# Generated by FakeRAM 2.0
VERSION 5.7 ;
BUSBITCHARS "[]" ;
PROPERTYDEFINITIONS
  MACRO width INTEGER ;
  MACRO depth INTEGER ;
  MACRO banks INTEGER ;
END PROPERTYDEFINITIONS
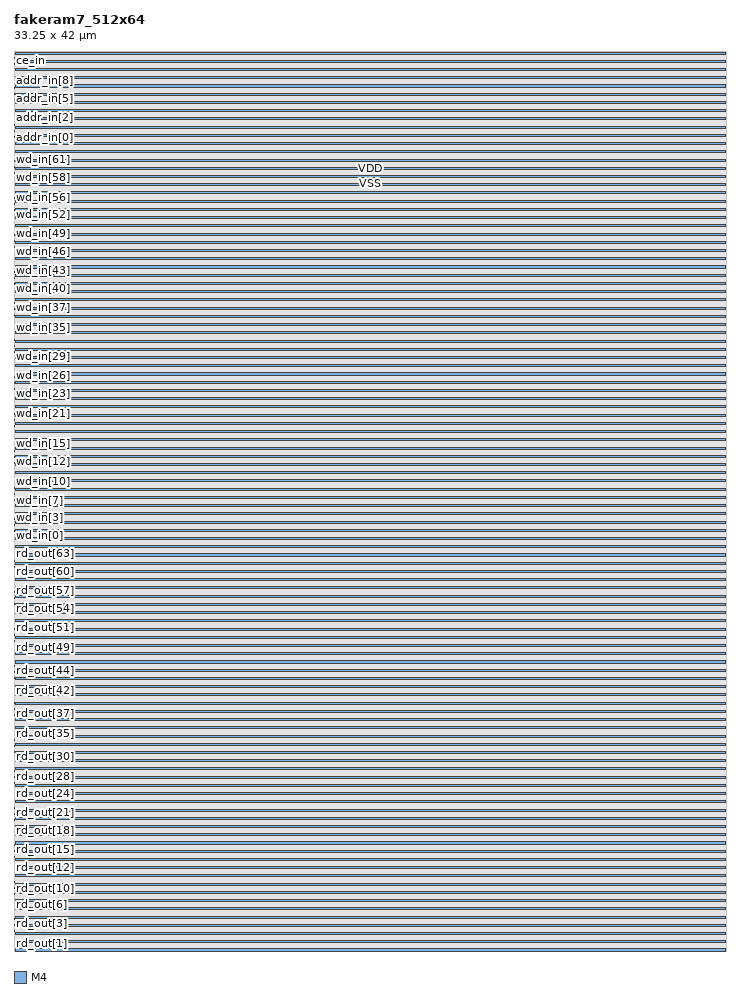
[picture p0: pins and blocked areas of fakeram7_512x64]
MACRO fakeram7_512x64
  PROPERTY width 64 ;
  PROPERTY depth 512 ;
  PROPERTY banks 4 ;
  FOREIGN fakeram7_512x64 0 0 ;
  SYMMETRY X Y R90 ;
  SIZE 33.2500 BY 42.0000 ;
  CLASS BLOCK ;
  PIN rd_out[0]
    DIRECTION OUTPUT ;
    USE SIGNAL ;
    PORT
      LAYER M4 ;
      RECT 0.00000 0.04800 0.02400 0.07200 ;
    END
  END rd_out[0]
  PIN rd_out[1]
    DIRECTION OUTPUT ;
    USE SIGNAL ;
    PORT
      LAYER M4 ;
      RECT 0.00000 0.33600 0.02400 0.36000 ;
    END
  END rd_out[1]
  PIN rd_out[2]
    DIRECTION OUTPUT ;
    USE SIGNAL ;
    PORT
      LAYER M4 ;
      RECT 0.00000 0.62400 0.02400 0.64800 ;
    END
  END rd_out[2]
  PIN rd_out[3]
    DIRECTION OUTPUT ;
    USE SIGNAL ;
    PORT
      LAYER M4 ;
      RECT 0.00000 0.91200 0.02400 0.93600 ;
    END
  END rd_out[3]
  PIN rd_out[4]
    DIRECTION OUTPUT ;
    USE SIGNAL ;
    PORT
      LAYER M4 ;
      RECT 0.00000 1.20000 0.02400 1.22400 ;
    END
  END rd_out[4]
  PIN rd_out[5]
    DIRECTION OUTPUT ;
    USE SIGNAL ;
    PORT
      LAYER M4 ;
      RECT 0.00000 1.48800 0.02400 1.51200 ;
    END
  END rd_out[5]
  PIN rd_out[6]
    DIRECTION OUTPUT ;
    USE SIGNAL ;
    PORT
      LAYER M4 ;
      RECT 0.00000 1.77600 0.02400 1.80000 ;
    END
  END rd_out[6]
  PIN rd_out[7]
    DIRECTION OUTPUT ;
    USE SIGNAL ;
    PORT
      LAYER M4 ;
      RECT 0.00000 2.06400 0.02400 2.08800 ;
    END
  END rd_out[7]
  PIN rd_out[8]
    DIRECTION OUTPUT ;
    USE SIGNAL ;
    PORT
      LAYER M4 ;
      RECT 0.00000 2.35200 0.02400 2.37600 ;
    END
  END rd_out[8]
  PIN rd_out[9]
    DIRECTION OUTPUT ;
    USE SIGNAL ;
    PORT
      LAYER M4 ;
      RECT 0.00000 2.64000 0.02400 2.66400 ;
    END
  END rd_out[9]
  PIN rd_out[10]
    DIRECTION OUTPUT ;
    USE SIGNAL ;
    PORT
      LAYER M4 ;
      RECT 0.00000 2.92800 0.02400 2.95200 ;
    END
  END rd_out[10]
  PIN rd_out[11]
    DIRECTION OUTPUT ;
    USE SIGNAL ;
    PORT
      LAYER M4 ;
      RECT 0.00000 3.21600 0.02400 3.24000 ;
    END
  END rd_out[11]
  PIN rd_out[12]
    DIRECTION OUTPUT ;
    USE SIGNAL ;
    PORT
      LAYER M4 ;
      RECT 0.00000 3.50400 0.02400 3.52800 ;
    END
  END rd_out[12]
  PIN rd_out[13]
    DIRECTION OUTPUT ;
    USE SIGNAL ;
    PORT
      LAYER M4 ;
      RECT 0.00000 3.79200 0.02400 3.81600 ;
    END
  END rd_out[13]
  PIN rd_out[14]
    DIRECTION OUTPUT ;
    USE SIGNAL ;
    PORT
      LAYER M4 ;
      RECT 0.00000 4.08000 0.02400 4.10400 ;
    END
  END rd_out[14]
  PIN rd_out[15]
    DIRECTION OUTPUT ;
    USE SIGNAL ;
    PORT
      LAYER M4 ;
      RECT 0.00000 4.36800 0.02400 4.39200 ;
    END
  END rd_out[15]
  PIN rd_out[16]
    DIRECTION OUTPUT ;
    USE SIGNAL ;
    PORT
      LAYER M4 ;
      RECT 0.00000 4.65600 0.02400 4.68000 ;
    END
  END rd_out[16]
  PIN rd_out[17]
    DIRECTION OUTPUT ;
    USE SIGNAL ;
    PORT
      LAYER M4 ;
      RECT 0.00000 4.94400 0.02400 4.96800 ;
    END
  END rd_out[17]
  PIN rd_out[18]
    DIRECTION OUTPUT ;
    USE SIGNAL ;
    PORT
      LAYER M4 ;
      RECT 0.00000 5.23200 0.02400 5.25600 ;
    END
  END rd_out[18]
  PIN rd_out[19]
    DIRECTION OUTPUT ;
    USE SIGNAL ;
    PORT
      LAYER M4 ;
      RECT 0.00000 5.52000 0.02400 5.54400 ;
    END
  END rd_out[19]
  PIN rd_out[20]
    DIRECTION OUTPUT ;
    USE SIGNAL ;
    PORT
      LAYER M4 ;
      RECT 0.00000 5.80800 0.02400 5.83200 ;
    END
  END rd_out[20]
  PIN rd_out[21]
    DIRECTION OUTPUT ;
    USE SIGNAL ;
    PORT
      LAYER M4 ;
      RECT 0.00000 6.09600 0.02400 6.12000 ;
    END
  END rd_out[21]
  PIN rd_out[22]
    DIRECTION OUTPUT ;
    USE SIGNAL ;
    PORT
      LAYER M4 ;
      RECT 0.00000 6.38400 0.02400 6.40800 ;
    END
  END rd_out[22]
  PIN rd_out[23]
    DIRECTION OUTPUT ;
    USE SIGNAL ;
    PORT
      LAYER M4 ;
      RECT 0.00000 6.67200 0.02400 6.69600 ;
    END
  END rd_out[23]
  PIN rd_out[24]
    DIRECTION OUTPUT ;
    USE SIGNAL ;
    PORT
      LAYER M4 ;
      RECT 0.00000 6.96000 0.02400 6.98400 ;
    END
  END rd_out[24]
  PIN rd_out[25]
    DIRECTION OUTPUT ;
    USE SIGNAL ;
    PORT
      LAYER M4 ;
      RECT 0.00000 7.24800 0.02400 7.27200 ;
    END
  END rd_out[25]
  PIN rd_out[26]
    DIRECTION OUTPUT ;
    USE SIGNAL ;
    PORT
      LAYER M4 ;
      RECT 0.00000 7.53600 0.02400 7.56000 ;
    END
  END rd_out[26]
  PIN rd_out[27]
    DIRECTION OUTPUT ;
    USE SIGNAL ;
    PORT
      LAYER M4 ;
      RECT 0.00000 7.82400 0.02400 7.84800 ;
    END
  END rd_out[27]
  PIN rd_out[28]
    DIRECTION OUTPUT ;
    USE SIGNAL ;
    PORT
      LAYER M4 ;
      RECT 0.00000 8.11200 0.02400 8.13600 ;
    END
  END rd_out[28]
  PIN rd_out[29]
    DIRECTION OUTPUT ;
    USE SIGNAL ;
    PORT
      LAYER M4 ;
      RECT 0.00000 8.40000 0.02400 8.42400 ;
    END
  END rd_out[29]
  PIN rd_out[30]
    DIRECTION OUTPUT ;
    USE SIGNAL ;
    PORT
      LAYER M4 ;
      RECT 0.00000 8.68800 0.02400 8.71200 ;
    END
  END rd_out[30]
  PIN rd_out[31]
    DIRECTION OUTPUT ;
    USE SIGNAL ;
    PORT
      LAYER M4 ;
      RECT 0.00000 8.97600 0.02400 9.00000 ;
    END
  END rd_out[31]
  PIN rd_out[32]
    DIRECTION OUTPUT ;
    USE SIGNAL ;
    PORT
      LAYER M4 ;
      RECT 0.00000 9.26400 0.02400 9.28800 ;
    END
  END rd_out[32]
  PIN rd_out[33]
    DIRECTION OUTPUT ;
    USE SIGNAL ;
    PORT
      LAYER M4 ;
      RECT 0.00000 9.55200 0.02400 9.57600 ;
    END
  END rd_out[33]
  PIN rd_out[34]
    DIRECTION OUTPUT ;
    USE SIGNAL ;
    PORT
      LAYER M4 ;
      RECT 0.00000 9.84000 0.02400 9.86400 ;
    END
  END rd_out[34]
  PIN rd_out[35]
    DIRECTION OUTPUT ;
    USE SIGNAL ;
    PORT
      LAYER M4 ;
      RECT 0.00000 10.12800 0.02400 10.15200 ;
    END
  END rd_out[35]
  PIN rd_out[36]
    DIRECTION OUTPUT ;
    USE SIGNAL ;
    PORT
      LAYER M4 ;
      RECT 0.00000 10.41600 0.02400 10.44000 ;
    END
  END rd_out[36]
  PIN rd_out[37]
    DIRECTION OUTPUT ;
    USE SIGNAL ;
    PORT
      LAYER M4 ;
      RECT 0.00000 10.70400 0.02400 10.72800 ;
    END
  END rd_out[37]
  PIN rd_out[38]
    DIRECTION OUTPUT ;
    USE SIGNAL ;
    PORT
      LAYER M4 ;
      RECT 0.00000 10.99200 0.02400 11.01600 ;
    END
  END rd_out[38]
  PIN rd_out[39]
    DIRECTION OUTPUT ;
    USE SIGNAL ;
    PORT
      LAYER M4 ;
      RECT 0.00000 11.28000 0.02400 11.30400 ;
    END
  END rd_out[39]
  PIN rd_out[40]
    DIRECTION OUTPUT ;
    USE SIGNAL ;
    PORT
      LAYER M4 ;
      RECT 0.00000 11.56800 0.02400 11.59200 ;
    END
  END rd_out[40]
  PIN rd_out[41]
    DIRECTION OUTPUT ;
    USE SIGNAL ;
    PORT
      LAYER M4 ;
      RECT 0.00000 11.85600 0.02400 11.88000 ;
    END
  END rd_out[41]
  PIN rd_out[42]
    DIRECTION OUTPUT ;
    USE SIGNAL ;
    PORT
      LAYER M4 ;
      RECT 0.00000 12.14400 0.02400 12.16800 ;
    END
  END rd_out[42]
  PIN rd_out[43]
    DIRECTION OUTPUT ;
    USE SIGNAL ;
    PORT
      LAYER M4 ;
      RECT 0.00000 12.43200 0.02400 12.45600 ;
    END
  END rd_out[43]
  PIN rd_out[44]
    DIRECTION OUTPUT ;
    USE SIGNAL ;
    PORT
      LAYER M4 ;
      RECT 0.00000 12.72000 0.02400 12.74400 ;
    END
  END rd_out[44]
  PIN rd_out[45]
    DIRECTION OUTPUT ;
    USE SIGNAL ;
    PORT
      LAYER M4 ;
      RECT 0.00000 13.00800 0.02400 13.03200 ;
    END
  END rd_out[45]
  PIN rd_out[46]
    DIRECTION OUTPUT ;
    USE SIGNAL ;
    PORT
      LAYER M4 ;
      RECT 0.00000 13.29600 0.02400 13.32000 ;
    END
  END rd_out[46]
  PIN rd_out[47]
    DIRECTION OUTPUT ;
    USE SIGNAL ;
    PORT
      LAYER M4 ;
      RECT 0.00000 13.58400 0.02400 13.60800 ;
    END
  END rd_out[47]
  PIN rd_out[48]
    DIRECTION OUTPUT ;
    USE SIGNAL ;
    PORT
      LAYER M4 ;
      RECT 0.00000 13.87200 0.02400 13.89600 ;
    END
  END rd_out[48]
  PIN rd_out[49]
    DIRECTION OUTPUT ;
    USE SIGNAL ;
    PORT
      LAYER M4 ;
      RECT 0.00000 14.16000 0.02400 14.18400 ;
    END
  END rd_out[49]
  PIN rd_out[50]
    DIRECTION OUTPUT ;
    USE SIGNAL ;
    PORT
      LAYER M4 ;
      RECT 0.00000 14.44800 0.02400 14.47200 ;
    END
  END rd_out[50]
  PIN rd_out[51]
    DIRECTION OUTPUT ;
    USE SIGNAL ;
    PORT
      LAYER M4 ;
      RECT 0.00000 14.73600 0.02400 14.76000 ;
    END
  END rd_out[51]
  PIN rd_out[52]
    DIRECTION OUTPUT ;
    USE SIGNAL ;
    PORT
      LAYER M4 ;
      RECT 0.00000 15.02400 0.02400 15.04800 ;
    END
  END rd_out[52]
  PIN rd_out[53]
    DIRECTION OUTPUT ;
    USE SIGNAL ;
    PORT
      LAYER M4 ;
      RECT 0.00000 15.31200 0.02400 15.33600 ;
    END
  END rd_out[53]
  PIN rd_out[54]
    DIRECTION OUTPUT ;
    USE SIGNAL ;
    PORT
      LAYER M4 ;
      RECT 0.00000 15.60000 0.02400 15.62400 ;
    END
  END rd_out[54]
  PIN rd_out[55]
    DIRECTION OUTPUT ;
    USE SIGNAL ;
    PORT
      LAYER M4 ;
      RECT 0.00000 15.88800 0.02400 15.91200 ;
    END
  END rd_out[55]
  PIN rd_out[56]
    DIRECTION OUTPUT ;
    USE SIGNAL ;
    PORT
      LAYER M4 ;
      RECT 0.00000 16.17600 0.02400 16.20000 ;
    END
  END rd_out[56]
  PIN rd_out[57]
    DIRECTION OUTPUT ;
    USE SIGNAL ;
    PORT
      LAYER M4 ;
      RECT 0.00000 16.46400 0.02400 16.48800 ;
    END
  END rd_out[57]
  PIN rd_out[58]
    DIRECTION OUTPUT ;
    USE SIGNAL ;
    PORT
      LAYER M4 ;
      RECT 0.00000 16.75200 0.02400 16.77600 ;
    END
  END rd_out[58]
  PIN rd_out[59]
    DIRECTION OUTPUT ;
    USE SIGNAL ;
    PORT
      LAYER M4 ;
      RECT 0.00000 17.04000 0.02400 17.06400 ;
    END
  END rd_out[59]
  PIN rd_out[60]
    DIRECTION OUTPUT ;
    USE SIGNAL ;
    PORT
      LAYER M4 ;
      RECT 0.00000 17.32800 0.02400 17.35200 ;
    END
  END rd_out[60]
  PIN rd_out[61]
    DIRECTION OUTPUT ;
    USE SIGNAL ;
    PORT
      LAYER M4 ;
      RECT 0.00000 17.61600 0.02400 17.64000 ;
    END
  END rd_out[61]
  PIN rd_out[62]
    DIRECTION OUTPUT ;
    USE SIGNAL ;
    PORT
      LAYER M4 ;
      RECT 0.00000 17.90400 0.02400 17.92800 ;
    END
  END rd_out[62]
  PIN rd_out[63]
    DIRECTION OUTPUT ;
    USE SIGNAL ;
    PORT
      LAYER M4 ;
      RECT 0.00000 18.19200 0.02400 18.21600 ;
    END
  END rd_out[63]
  PIN wd_in[0]
    DIRECTION INPUT ;
    USE SIGNAL ;
    PORT
      LAYER M4 ;
      RECT 0.00000 19.00800 0.02400 19.03200 ;
    END
  END wd_in[0]
  PIN wd_in[1]
    DIRECTION INPUT ;
    USE SIGNAL ;
    PORT
      LAYER M4 ;
      RECT 0.00000 19.29600 0.02400 19.32000 ;
    END
  END wd_in[1]
  PIN wd_in[2]
    DIRECTION INPUT ;
    USE SIGNAL ;
    PORT
      LAYER M4 ;
      RECT 0.00000 19.58400 0.02400 19.60800 ;
    END
  END wd_in[2]
  PIN wd_in[3]
    DIRECTION INPUT ;
    USE SIGNAL ;
    PORT
      LAYER M4 ;
      RECT 0.00000 19.87200 0.02400 19.89600 ;
    END
  END wd_in[3]
  PIN wd_in[4]
    DIRECTION INPUT ;
    USE SIGNAL ;
    PORT
      LAYER M4 ;
      RECT 0.00000 20.16000 0.02400 20.18400 ;
    END
  END wd_in[4]
  PIN wd_in[5]
    DIRECTION INPUT ;
    USE SIGNAL ;
    PORT
      LAYER M4 ;
      RECT 0.00000 20.44800 0.02400 20.47200 ;
    END
  END wd_in[5]
  PIN wd_in[6]
    DIRECTION INPUT ;
    USE SIGNAL ;
    PORT
      LAYER M4 ;
      RECT 0.00000 20.73600 0.02400 20.76000 ;
    END
  END wd_in[6]
  PIN wd_in[7]
    DIRECTION INPUT ;
    USE SIGNAL ;
    PORT
      LAYER M4 ;
      RECT 0.00000 21.02400 0.02400 21.04800 ;
    END
  END wd_in[7]
  PIN wd_in[8]
    DIRECTION INPUT ;
    USE SIGNAL ;
    PORT
      LAYER M4 ;
      RECT 0.00000 21.31200 0.02400 21.33600 ;
    END
  END wd_in[8]
  PIN wd_in[9]
    DIRECTION INPUT ;
    USE SIGNAL ;
    PORT
      LAYER M4 ;
      RECT 0.00000 21.60000 0.02400 21.62400 ;
    END
  END wd_in[9]
  PIN wd_in[10]
    DIRECTION INPUT ;
    USE SIGNAL ;
    PORT
      LAYER M4 ;
      RECT 0.00000 21.88800 0.02400 21.91200 ;
    END
  END wd_in[10]
  PIN wd_in[11]
    DIRECTION INPUT ;
    USE SIGNAL ;
    PORT
      LAYER M4 ;
      RECT 0.00000 22.17600 0.02400 22.20000 ;
    END
  END wd_in[11]
  PIN wd_in[12]
    DIRECTION INPUT ;
    USE SIGNAL ;
    PORT
      LAYER M4 ;
      RECT 0.00000 22.46400 0.02400 22.48800 ;
    END
  END wd_in[12]
  PIN wd_in[13]
    DIRECTION INPUT ;
    USE SIGNAL ;
    PORT
      LAYER M4 ;
      RECT 0.00000 22.75200 0.02400 22.77600 ;
    END
  END wd_in[13]
  PIN wd_in[14]
    DIRECTION INPUT ;
    USE SIGNAL ;
    PORT
      LAYER M4 ;
      RECT 0.00000 23.04000 0.02400 23.06400 ;
    END
  END wd_in[14]
  PIN wd_in[15]
    DIRECTION INPUT ;
    USE SIGNAL ;
    PORT
      LAYER M4 ;
      RECT 0.00000 23.32800 0.02400 23.35200 ;
    END
  END wd_in[15]
  PIN wd_in[16]
    DIRECTION INPUT ;
    USE SIGNAL ;
    PORT
      LAYER M4 ;
      RECT 0.00000 23.61600 0.02400 23.64000 ;
    END
  END wd_in[16]
  PIN wd_in[17]
    DIRECTION INPUT ;
    USE SIGNAL ;
    PORT
      LAYER M4 ;
      RECT 0.00000 23.90400 0.02400 23.92800 ;
    END
  END wd_in[17]
  PIN wd_in[18]
    DIRECTION INPUT ;
    USE SIGNAL ;
    PORT
      LAYER M4 ;
      RECT 0.00000 24.19200 0.02400 24.21600 ;
    END
  END wd_in[18]
  PIN wd_in[19]
    DIRECTION INPUT ;
    USE SIGNAL ;
    PORT
      LAYER M4 ;
      RECT 0.00000 24.48000 0.02400 24.50400 ;
    END
  END wd_in[19]
  PIN wd_in[20]
    DIRECTION INPUT ;
    USE SIGNAL ;
    PORT
      LAYER M4 ;
      RECT 0.00000 24.76800 0.02400 24.79200 ;
    END
  END wd_in[20]
  PIN wd_in[21]
    DIRECTION INPUT ;
    USE SIGNAL ;
    PORT
      LAYER M4 ;
      RECT 0.00000 25.05600 0.02400 25.08000 ;
    END
  END wd_in[21]
  PIN wd_in[22]
    DIRECTION INPUT ;
    USE SIGNAL ;
    PORT
      LAYER M4 ;
      RECT 0.00000 25.34400 0.02400 25.36800 ;
    END
  END wd_in[22]
  PIN wd_in[23]
    DIRECTION INPUT ;
    USE SIGNAL ;
    PORT
      LAYER M4 ;
      RECT 0.00000 25.63200 0.02400 25.65600 ;
    END
  END wd_in[23]
  PIN wd_in[24]
    DIRECTION INPUT ;
    USE SIGNAL ;
    PORT
      LAYER M4 ;
      RECT 0.00000 25.92000 0.02400 25.94400 ;
    END
  END wd_in[24]
  PIN wd_in[25]
    DIRECTION INPUT ;
    USE SIGNAL ;
    PORT
      LAYER M4 ;
      RECT 0.00000 26.20800 0.02400 26.23200 ;
    END
  END wd_in[25]
  PIN wd_in[26]
    DIRECTION INPUT ;
    USE SIGNAL ;
    PORT
      LAYER M4 ;
      RECT 0.00000 26.49600 0.02400 26.52000 ;
    END
  END wd_in[26]
  PIN wd_in[27]
    DIRECTION INPUT ;
    USE SIGNAL ;
    PORT
      LAYER M4 ;
      RECT 0.00000 26.78400 0.02400 26.80800 ;
    END
  END wd_in[27]
  PIN wd_in[28]
    DIRECTION INPUT ;
    USE SIGNAL ;
    PORT
      LAYER M4 ;
      RECT 0.00000 27.07200 0.02400 27.09600 ;
    END
  END wd_in[28]
  PIN wd_in[29]
    DIRECTION INPUT ;
    USE SIGNAL ;
    PORT
      LAYER M4 ;
      RECT 0.00000 27.36000 0.02400 27.38400 ;
    END
  END wd_in[29]
  PIN wd_in[30]
    DIRECTION INPUT ;
    USE SIGNAL ;
    PORT
      LAYER M4 ;
      RECT 0.00000 27.64800 0.02400 27.67200 ;
    END
  END wd_in[30]
  PIN wd_in[31]
    DIRECTION INPUT ;
    USE SIGNAL ;
    PORT
      LAYER M4 ;
      RECT 0.00000 27.93600 0.02400 27.96000 ;
    END
  END wd_in[31]
  PIN wd_in[32]
    DIRECTION INPUT ;
    USE SIGNAL ;
    PORT
      LAYER M4 ;
      RECT 0.00000 28.22400 0.02400 28.24800 ;
    END
  END wd_in[32]
  PIN wd_in[33]
    DIRECTION INPUT ;
    USE SIGNAL ;
    PORT
      LAYER M4 ;
      RECT 0.00000 28.51200 0.02400 28.53600 ;
    END
  END wd_in[33]
  PIN wd_in[34]
    DIRECTION INPUT ;
    USE SIGNAL ;
    PORT
      LAYER M4 ;
      RECT 0.00000 28.80000 0.02400 28.82400 ;
    END
  END wd_in[34]
  PIN wd_in[35]
    DIRECTION INPUT ;
    USE SIGNAL ;
    PORT
      LAYER M4 ;
      RECT 0.00000 29.08800 0.02400 29.11200 ;
    END
  END wd_in[35]
  PIN wd_in[36]
    DIRECTION INPUT ;
    USE SIGNAL ;
    PORT
      LAYER M4 ;
      RECT 0.00000 29.37600 0.02400 29.40000 ;
    END
  END wd_in[36]
  PIN wd_in[37]
    DIRECTION INPUT ;
    USE SIGNAL ;
    PORT
      LAYER M4 ;
      RECT 0.00000 29.66400 0.02400 29.68800 ;
    END
  END wd_in[37]
  PIN wd_in[38]
    DIRECTION INPUT ;
    USE SIGNAL ;
    PORT
      LAYER M4 ;
      RECT 0.00000 29.95200 0.02400 29.97600 ;
    END
  END wd_in[38]
  PIN wd_in[39]
    DIRECTION INPUT ;
    USE SIGNAL ;
    PORT
      LAYER M4 ;
      RECT 0.00000 30.24000 0.02400 30.26400 ;
    END
  END wd_in[39]
  PIN wd_in[40]
    DIRECTION INPUT ;
    USE SIGNAL ;
    PORT
      LAYER M4 ;
      RECT 0.00000 30.52800 0.02400 30.55200 ;
    END
  END wd_in[40]
  PIN wd_in[41]
    DIRECTION INPUT ;
    USE SIGNAL ;
    PORT
      LAYER M4 ;
      RECT 0.00000 30.81600 0.02400 30.84000 ;
    END
  END wd_in[41]
  PIN wd_in[42]
    DIRECTION INPUT ;
    USE SIGNAL ;
    PORT
      LAYER M4 ;
      RECT 0.00000 31.10400 0.02400 31.12800 ;
    END
  END wd_in[42]
  PIN wd_in[43]
    DIRECTION INPUT ;
    USE SIGNAL ;
    PORT
      LAYER M4 ;
      RECT 0.00000 31.39200 0.02400 31.41600 ;
    END
  END wd_in[43]
  PIN wd_in[44]
    DIRECTION INPUT ;
    USE SIGNAL ;
    PORT
      LAYER M4 ;
      RECT 0.00000 31.68000 0.02400 31.70400 ;
    END
  END wd_in[44]
  PIN wd_in[45]
    DIRECTION INPUT ;
    USE SIGNAL ;
    PORT
      LAYER M4 ;
      RECT 0.00000 31.96800 0.02400 31.99200 ;
    END
  END wd_in[45]
  PIN wd_in[46]
    DIRECTION INPUT ;
    USE SIGNAL ;
    PORT
      LAYER M4 ;
      RECT 0.00000 32.25600 0.02400 32.28000 ;
    END
  END wd_in[46]
  PIN wd_in[47]
    DIRECTION INPUT ;
    USE SIGNAL ;
    PORT
      LAYER M4 ;
      RECT 0.00000 32.54400 0.02400 32.56800 ;
    END
  END wd_in[47]
  PIN wd_in[48]
    DIRECTION INPUT ;
    USE SIGNAL ;
    PORT
      LAYER M4 ;
      RECT 0.00000 32.83200 0.02400 32.85600 ;
    END
  END wd_in[48]
  PIN wd_in[49]
    DIRECTION INPUT ;
    USE SIGNAL ;
    PORT
      LAYER M4 ;
      RECT 0.00000 33.12000 0.02400 33.14400 ;
    END
  END wd_in[49]
  PIN wd_in[50]
    DIRECTION INPUT ;
    USE SIGNAL ;
    PORT
      LAYER M4 ;
      RECT 0.00000 33.40800 0.02400 33.43200 ;
    END
  END wd_in[50]
  PIN wd_in[51]
    DIRECTION INPUT ;
    USE SIGNAL ;
    PORT
      LAYER M4 ;
      RECT 0.00000 33.69600 0.02400 33.72000 ;
    END
  END wd_in[51]
  PIN wd_in[52]
    DIRECTION INPUT ;
    USE SIGNAL ;
    PORT
      LAYER M4 ;
      RECT 0.00000 33.98400 0.02400 34.00800 ;
    END
  END wd_in[52]
  PIN wd_in[53]
    DIRECTION INPUT ;
    USE SIGNAL ;
    PORT
      LAYER M4 ;
      RECT 0.00000 34.27200 0.02400 34.29600 ;
    END
  END wd_in[53]
  PIN wd_in[54]
    DIRECTION INPUT ;
    USE SIGNAL ;
    PORT
      LAYER M4 ;
      RECT 0.00000 34.56000 0.02400 34.58400 ;
    END
  END wd_in[54]
  PIN wd_in[55]
    DIRECTION INPUT ;
    USE SIGNAL ;
    PORT
      LAYER M4 ;
      RECT 0.00000 34.84800 0.02400 34.87200 ;
    END
  END wd_in[55]
  PIN wd_in[56]
    DIRECTION INPUT ;
    USE SIGNAL ;
    PORT
      LAYER M4 ;
      RECT 0.00000 35.13600 0.02400 35.16000 ;
    END
  END wd_in[56]
  PIN wd_in[57]
    DIRECTION INPUT ;
    USE SIGNAL ;
    PORT
      LAYER M4 ;
      RECT 0.00000 35.42400 0.02400 35.44800 ;
    END
  END wd_in[57]
  PIN wd_in[58]
    DIRECTION INPUT ;
    USE SIGNAL ;
    PORT
      LAYER M4 ;
      RECT 0.00000 35.71200 0.02400 35.73600 ;
    END
  END wd_in[58]
  PIN wd_in[59]
    DIRECTION INPUT ;
    USE SIGNAL ;
    PORT
      LAYER M4 ;
      RECT 0.00000 36.00000 0.02400 36.02400 ;
    END
  END wd_in[59]
  PIN wd_in[60]
    DIRECTION INPUT ;
    USE SIGNAL ;
    PORT
      LAYER M4 ;
      RECT 0.00000 36.28800 0.02400 36.31200 ;
    END
  END wd_in[60]
  PIN wd_in[61]
    DIRECTION INPUT ;
    USE SIGNAL ;
    PORT
      LAYER M4 ;
      RECT 0.00000 36.57600 0.02400 36.60000 ;
    END
  END wd_in[61]
  PIN wd_in[62]
    DIRECTION INPUT ;
    USE SIGNAL ;
    PORT
      LAYER M4 ;
      RECT 0.00000 36.86400 0.02400 36.88800 ;
    END
  END wd_in[62]
  PIN wd_in[63]
    DIRECTION INPUT ;
    USE SIGNAL ;
    PORT
      LAYER M4 ;
      RECT 0.00000 37.15200 0.02400 37.17600 ;
    END
  END wd_in[63]
  PIN addr_in[0]
    DIRECTION INPUT ;
    USE SIGNAL ;
    PORT
      LAYER M4 ;
      RECT 0.00000 37.96800 0.02400 37.99200 ;
    END
  END addr_in[0]
  PIN addr_in[1]
    DIRECTION INPUT ;
    USE SIGNAL ;
    PORT
      LAYER M4 ;
      RECT 0.00000 38.25600 0.02400 38.28000 ;
    END
  END addr_in[1]
  PIN addr_in[2]
    DIRECTION INPUT ;
    USE SIGNAL ;
    PORT
      LAYER M4 ;
      RECT 0.00000 38.54400 0.02400 38.56800 ;
    END
  END addr_in[2]
  PIN addr_in[3]
    DIRECTION INPUT ;
    USE SIGNAL ;
    PORT
      LAYER M4 ;
      RECT 0.00000 38.83200 0.02400 38.85600 ;
    END
  END addr_in[3]
  PIN addr_in[4]
    DIRECTION INPUT ;
    USE SIGNAL ;
    PORT
      LAYER M4 ;
      RECT 0.00000 39.12000 0.02400 39.14400 ;
    END
  END addr_in[4]
  PIN addr_in[5]
    DIRECTION INPUT ;
    USE SIGNAL ;
    PORT
      LAYER M4 ;
      RECT 0.00000 39.40800 0.02400 39.43200 ;
    END
  END addr_in[5]
  PIN addr_in[6]
    DIRECTION INPUT ;
    USE SIGNAL ;
    PORT
      LAYER M4 ;
      RECT 0.00000 39.69600 0.02400 39.72000 ;
    END
  END addr_in[6]
  PIN addr_in[7]
    DIRECTION INPUT ;
    USE SIGNAL ;
    PORT
      LAYER M4 ;
      RECT 0.00000 39.98400 0.02400 40.00800 ;
    END
  END addr_in[7]
  PIN addr_in[8]
    DIRECTION INPUT ;
    USE SIGNAL ;
    PORT
      LAYER M4 ;
      RECT 0.00000 40.27200 0.02400 40.29600 ;
    END
  END addr_in[8]
  PIN we_in
    DIRECTION INPUT ;
    USE SIGNAL ;
    PORT
      LAYER M4 ;
      RECT 0.00000 41.08800 0.02400 41.11200 ;
    END
  END we_in
  PIN clk
    DIRECTION INPUT ;
    USE SIGNAL ;
    PORT
      LAYER M4 ;
      RECT 0.00000 41.37600 0.02400 41.40000 ;
    END
  END clk
  PIN ce_in
    DIRECTION INPUT ;
    USE SIGNAL ;
    PORT
      LAYER M4 ;
      RECT 0.00000 41.66400 0.02400 41.68800 ;
    END
  END ce_in
  PIN VDD
    DIRECTION INOUT ;
    USE POWER ;
    PORT
      LAYER M4 ;
      RECT 0.04800 0.38400 33.20200 0.48000 ;
      RECT 0.04800 1.15200 33.20200 1.24800 ;
      RECT 0.04800 1.92000 33.20200 2.01600 ;
      RECT 0.04800 2.68800 33.20200 2.78400 ;
      RECT 0.04800 3.45600 33.20200 3.55200 ;
      RECT 0.04800 4.22400 33.20200 4.32000 ;
      RECT 0.04800 4.99200 33.20200 5.08800 ;
      RECT 0.04800 5.76000 33.20200 5.85600 ;
      RECT 0.04800 6.52800 33.20200 6.62400 ;
      RECT 0.04800 7.29600 33.20200 7.39200 ;
      RECT 0.04800 8.06400 33.20200 8.16000 ;
      RECT 0.04800 8.83200 33.20200 8.92800 ;
      RECT 0.04800 9.60000 33.20200 9.69600 ;
      RECT 0.04800 10.36800 33.20200 10.46400 ;
      RECT 0.04800 11.13600 33.20200 11.23200 ;
      RECT 0.04800 11.90400 33.20200 12.00000 ;
      RECT 0.04800 12.67200 33.20200 12.76800 ;
      RECT 0.04800 13.44000 33.20200 13.53600 ;
      RECT 0.04800 14.20800 33.20200 14.30400 ;
      RECT 0.04800 14.97600 33.20200 15.07200 ;
      RECT 0.04800 15.74400 33.20200 15.84000 ;
      RECT 0.04800 16.51200 33.20200 16.60800 ;
      RECT 0.04800 17.28000 33.20200 17.37600 ;
      RECT 0.04800 18.04800 33.20200 18.14400 ;
      RECT 0.04800 18.81600 33.20200 18.91200 ;
      RECT 0.04800 19.58400 33.20200 19.68000 ;
      RECT 0.04800 20.35200 33.20200 20.44800 ;
      RECT 0.04800 21.12000 33.20200 21.21600 ;
      RECT 0.04800 21.88800 33.20200 21.98400 ;
      RECT 0.04800 22.65600 33.20200 22.75200 ;
      RECT 0.04800 23.42400 33.20200 23.52000 ;
      RECT 0.04800 24.19200 33.20200 24.28800 ;
      RECT 0.04800 24.96000 33.20200 25.05600 ;
      RECT 0.04800 25.72800 33.20200 25.82400 ;
      RECT 0.04800 26.49600 33.20200 26.59200 ;
      RECT 0.04800 27.26400 33.20200 27.36000 ;
      RECT 0.04800 28.03200 33.20200 28.12800 ;
      RECT 0.04800 28.80000 33.20200 28.89600 ;
      RECT 0.04800 29.56800 33.20200 29.66400 ;
      RECT 0.04800 30.33600 33.20200 30.43200 ;
      RECT 0.04800 31.10400 33.20200 31.20000 ;
      RECT 0.04800 31.87200 33.20200 31.96800 ;
      RECT 0.04800 32.64000 33.20200 32.73600 ;
      RECT 0.04800 33.40800 33.20200 33.50400 ;
      RECT 0.04800 34.17600 33.20200 34.27200 ;
      RECT 0.04800 34.94400 33.20200 35.04000 ;
      RECT 0.04800 35.71200 33.20200 35.80800 ;
      RECT 0.04800 36.48000 33.20200 36.57600 ;
      RECT 0.04800 37.24800 33.20200 37.34400 ;
      RECT 0.04800 38.01600 33.20200 38.11200 ;
      RECT 0.04800 38.78400 33.20200 38.88000 ;
      RECT 0.04800 39.55200 33.20200 39.64800 ;
      RECT 0.04800 40.32000 33.20200 40.41600 ;
      RECT 0.04800 41.08800 33.20200 41.18400 ;
      RECT 0.04800 41.85600 33.20200 41.95200 ;
    END
  END VDD
  PIN VSS
    DIRECTION INOUT ;
    USE GROUND ;
    PORT
      LAYER M4 ;
      RECT 0.04800 0.00000 33.20200 0.09600 ;
      RECT 0.04800 0.76800 33.20200 0.86400 ;
      RECT 0.04800 1.53600 33.20200 1.63200 ;
      RECT 0.04800 2.30400 33.20200 2.40000 ;
      RECT 0.04800 3.07200 33.20200 3.16800 ;
      RECT 0.04800 3.84000 33.20200 3.93600 ;
      RECT 0.04800 4.60800 33.20200 4.70400 ;
      RECT 0.04800 5.37600 33.20200 5.47200 ;
      RECT 0.04800 6.14400 33.20200 6.24000 ;
      RECT 0.04800 6.91200 33.20200 7.00800 ;
      RECT 0.04800 7.68000 33.20200 7.77600 ;
      RECT 0.04800 8.44800 33.20200 8.54400 ;
      RECT 0.04800 9.21600 33.20200 9.31200 ;
      RECT 0.04800 9.98400 33.20200 10.08000 ;
      RECT 0.04800 10.75200 33.20200 10.84800 ;
      RECT 0.04800 11.52000 33.20200 11.61600 ;
      RECT 0.04800 12.28800 33.20200 12.38400 ;
      RECT 0.04800 13.05600 33.20200 13.15200 ;
      RECT 0.04800 13.82400 33.20200 13.92000 ;
      RECT 0.04800 14.59200 33.20200 14.68800 ;
      RECT 0.04800 15.36000 33.20200 15.45600 ;
      RECT 0.04800 16.12800 33.20200 16.22400 ;
      RECT 0.04800 16.89600 33.20200 16.99200 ;
      RECT 0.04800 17.66400 33.20200 17.76000 ;
      RECT 0.04800 18.43200 33.20200 18.52800 ;
      RECT 0.04800 19.20000 33.20200 19.29600 ;
      RECT 0.04800 19.96800 33.20200 20.06400 ;
      RECT 0.04800 20.73600 33.20200 20.83200 ;
      RECT 0.04800 21.50400 33.20200 21.60000 ;
      RECT 0.04800 22.27200 33.20200 22.36800 ;
      RECT 0.04800 23.04000 33.20200 23.13600 ;
      RECT 0.04800 23.80800 33.20200 23.90400 ;
      RECT 0.04800 24.57600 33.20200 24.67200 ;
      RECT 0.04800 25.34400 33.20200 25.44000 ;
      RECT 0.04800 26.11200 33.20200 26.20800 ;
      RECT 0.04800 26.88000 33.20200 26.97600 ;
      RECT 0.04800 27.64800 33.20200 27.74400 ;
      RECT 0.04800 28.41600 33.20200 28.51200 ;
      RECT 0.04800 29.18400 33.20200 29.28000 ;
      RECT 0.04800 29.95200 33.20200 30.04800 ;
      RECT 0.04800 30.72000 33.20200 30.81600 ;
      RECT 0.04800 31.48800 33.20200 31.58400 ;
      RECT 0.04800 32.25600 33.20200 32.35200 ;
      RECT 0.04800 33.02400 33.20200 33.12000 ;
      RECT 0.04800 33.79200 33.20200 33.88800 ;
      RECT 0.04800 34.56000 33.20200 34.65600 ;
      RECT 0.04800 35.32800 33.20200 35.42400 ;
      RECT 0.04800 36.09600 33.20200 36.19200 ;
      RECT 0.04800 36.86400 33.20200 36.96000 ;
      RECT 0.04800 37.63200 33.20200 37.72800 ;
      RECT 0.04800 38.40000 33.20200 38.49600 ;
      RECT 0.04800 39.16800 33.20200 39.26400 ;
      RECT 0.04800 39.93600 33.20200 40.03200 ;
      RECT 0.04800 40.70400 33.20200 40.80000 ;
      RECT 0.04800 41.47200 33.20200 41.56800 ;
    END
  END VSS
  OBS
    LAYER M1 ;
    RECT 0 0 33.25000 42.00000 ;
    LAYER M2 ;
    RECT 0 0 33.25000 42.00000 ;
    LAYER M3 ;
    RECT 0 0 33.25000 42.00000 ;
    LAYER M4 ;
    RECT 0 0 33.25000 42.00000 ;
  END
END fakeram7_512x64

END LIBRARY
